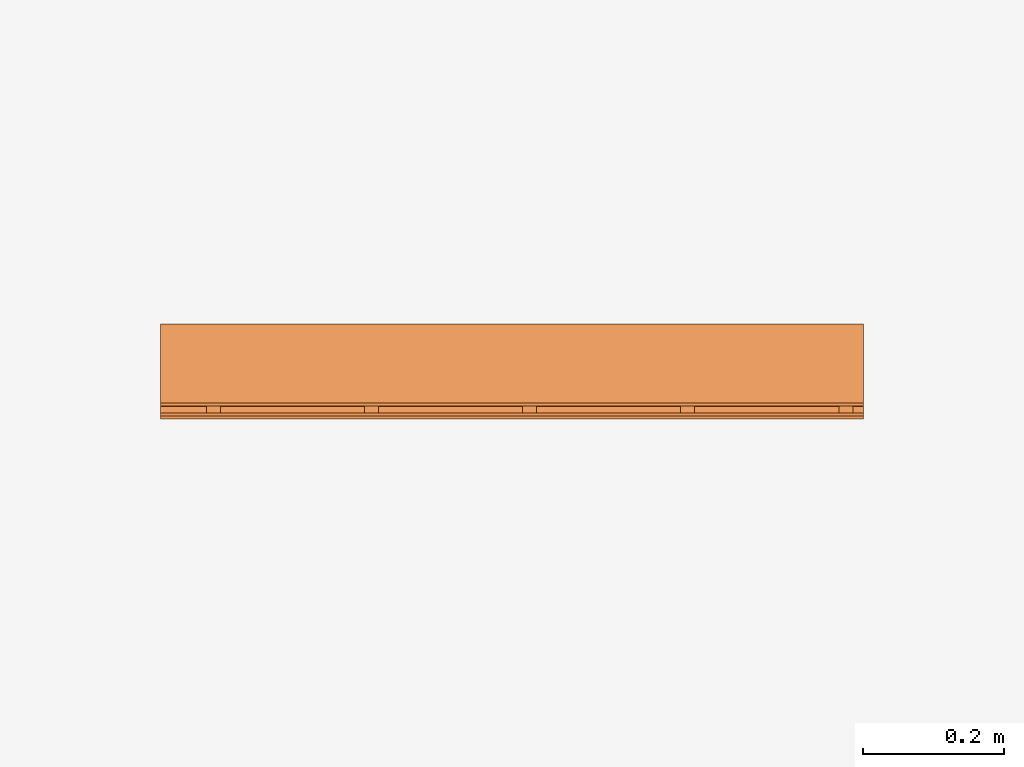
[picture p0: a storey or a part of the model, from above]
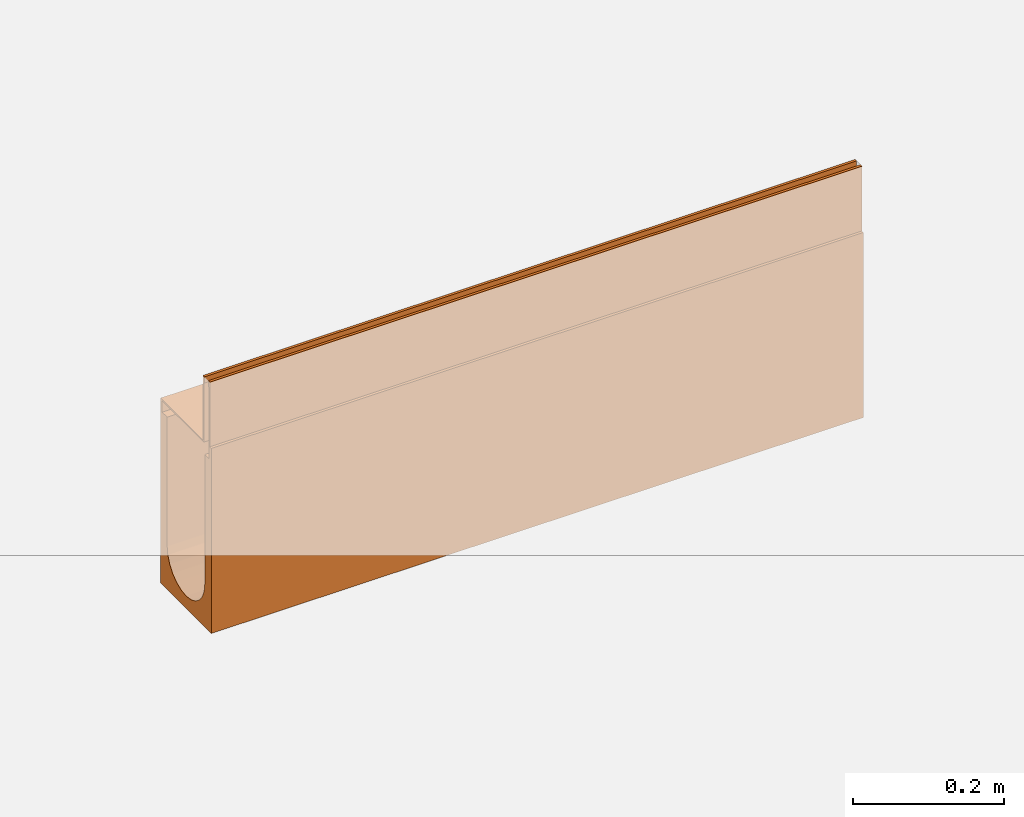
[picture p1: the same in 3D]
Properties of the parts of a building model (IFC2X3)

# File
Description: ViewDefinition [CoordinationView]
File name: 23300 - No 30.0 Constant Depth Channel - 1000mm LG - Invert Depth 280mm.ifc
Time: 2013-10-31T17:34:53
Written by: Autodesk Revit 2013
Made in: 20120221_2030(x64)

# IfcProject, Project Number
LongName: Project Name; Phase: Project Status

# IfcSite, Default
RefLatitude: 42, 21, 30, 344238; RefLongitude: -71, -3, -35, -194702; RefElevation: 0 mm

# IfcBuilding
Pset_BuildingCommon - NumberOfStoreys: 1
Other - Project Name: Project Name; Project Status: Project Status; Project Number: Project Number; Project Address: ## Street City, State Zip; Project Issue Date: Issue Date; Client Name: Owner

# IfcBuildingStorey, Level 1
LongName: Level 1; Elevation: 0 mm
Graphics - Symbol: M_Level Head - Circle: M_Level Head - Circle; Line Weight: 1; Color: 0; Symbol at End 1 Default: no; Line Pattern: Center; Symbol at End 2 Default: yes
Constraints - Elevation Base: 0; Elevation: 0 mm
Identity Data - Name: Level 1; Structural: no; Building Story: yes
Dimensions - Computation Height: 0 mm

# IfcBuildingElementProxy: 23300 - No 30.0 Constant Depth Channel - 1000mm LG - Invert Depth 280mm, Civil-Drainage-Channel-ACO-MultiDrain-M100D-Brickslot-Channel-System:23300 - No 30.0 Constant Depth Channel - 1000mm LG - Invert Depth 280mm:23300 - No 30.0 Constant Depth Channel - 1000mm LG - Invert Depth 280mm:196059
In: Level 1
Material: Steel, Galvanized, Vienite® Synthetic Resin Concrete
Phasing - Phase Created: New Construction
Construction - 23465_Load Class D400_Brickslot Grating_Galvanized Steel_1000mm Long: yes; 23467_Load Class D400_Brickslot Access Unit_Galvanised Steel_500mm Long: no; 23460_Load Class C250_Brickslot Grating_Galvanized Steel_1000mm Long: no; 23462_Load Class C250_Brickslot Access Unit_Galvanised Steel_500mm Long: no; 23461_Load Class C250_Brickslot Grating_Galvanized Steel_500mm Long: no; 23404_Universal Endcap (Male End): no; 23404_Universal Endcap (Female End): no; 23466_Load Class D400_Brickslot Grating_Galvanized Steel_500mm Long: no; Constant Depth Junction Channel: no; Shallow Depth Channel: no; Constant Depth Channel: yes; Sloping Channel: no; Shallow Depth Channel with seal: no; 23410_Sump Unit: no
Dimensions - FloorCut_Length: -1000 mm; Custom_Void_length: 0 mm; Length: 1000 mm; Brickslot Void Length: 1000 mm; Volume: 13742822 mm3; Brickslot Access Unit Void Depth: -6500 mm; EndCap Position: 1000 mm; Brickslot Access Unit Void Bottom Depth: -6605 mm; Brickslot Void Depth: 0 mm; Access_Custom_Void_Length: 0 mm; FloorCut_Width: 135 mm; Brickslot Access Unit Floor Cut Length: 500 mm; SlopingEndInvertDepth: 180 mm; Floor Cut Gap: 105 mm; GratingLength: -1000 mm; ShallowInvDepth: 55 mm; Length Drain: -1000 mm; SlopingInvertDepth: 175 mm; Depth: 300 mm; SlopingOverallDepth: 245 mm; SlopingEndOverallDepth: 250 mm; InvDepth: 230 mm; FloorCut_Depth: 300 mm; EndCap_Height: 300 mm; ShallowOverallDepth: 75 mm
Constraints - Level: Level: Level 1; Moves With Nearby Elements: no
Pset_BuildingElementProxyCommon - Reference: 23300 - No 30.0 Constant Depth Channel - 1000mm LG - Invert Depth 280mm
Model Properties - Brickslot Access Unit Product code 23462: Load Class C250 - Brickslot Access Unit Galvanised Steel - 500mm long x 105mm high - 10mm Slot - Intake area - 10000mm²/m - 6.4 Kg; Brickslot Grating Product code 23461: Load Class C250 - Brickslot Galvanised Steel - 500mm long x 105mm high - 10mm Slot - Intake area - 10000mm²/m -3.3 Kg; Brickslot Grating Product code 23460: Load Class C250 - Brickslot Galvanised Steel - 1000mm long x 105mm high - 10mm Slot - Intake area - 10000mm²/m - 6.6 Kg; Brickslot Access Unit Product code 23467: Load Class D400 - Brickslot Access Unit Galvanised Steel - 500mm long x 105mm high - 10mm Slot - Intake area - 10000mm²/m - 6.4 Kg; Brickslot Grating Product code 23465: Load Class D400 - Brickslot Galvanised Steel - 1000mm long x 105mm high - 10mm Slot - Intake area - 10000mm²/m - 6.6 Kg; End Cap Product code 23404: No 306 Universal End Cap - 135mm wide x 300mm long - Spigot Ø110mm x 50mm long - Silver - Polypropylene - 0.16kg; Brickslot Grating Product code 23466: Load Class D400 - Brickslot Galvanised Steel - 500mm long x 105mm high - 10mm Slot - Intake area - 10000mm²/m - 3.3 Kg
Green Building Properties - Channel Recycled Material Content: 20% minimum; Edge Rail Recyclable: Fully recyclable; Channel Recyclable: Fully recyclable; Edge Rail Recycled Material Content: Between 40% - 90%
Identity Data - Product Code: 23300; Watermark 2: This file is water marked and users are prohibited to reproduce, adapt, distribute this information; OmniClass Number: 23.70.50.24; Watermarked With: BIM Manager Premium Suite; Maintenance guidelines: http://www.aco.co.uk/download.php?id=173; Watermark 1: This file is the property of ACO Technologies PLC; URL: www.aco.co.uk; Assembly Description: Rain Water Drainage; Model Description: Channel drainage system; e-mail Sales: customersupport@aco.co.uk; Product brochure: http://www.aco.co.uk/download.php?id=173; Price: POA - contact ACO; Telephone: +44 (0)1462 816666; Installation guidelines: http://www.aco.co.uk/download.php?id=173; Fax: +44 (0)1462 815895; Product Page URL: http://www.aco.co.uk/product_detail.php?id=58; e-mail Technical: technical@aco.co.uk; OmniClass Title: Rainwater Removal; Type Comments: ACO MultiDrain M100D 30.0 Constant Depth Channel 1000mm Long; Cost: 0; Address: ACO Business Park, Hitchin Road, Shefford, Bedfordshire, United Kingdom SG17 5TE; Manufacturer: ACO Technologies plc - ACO Water Management Division; Model: ACO MultiDrain MD Brickslot- M100D; Assembly Code: D2040
Materials and Finishes - Channel Colour: Brown; Channel Material: Vienite® Synthetic Resin Concrete; Edge Rail Colour: Silver; Edge Rail Material: Steel; Edge Rail Finish: Pre-galvanised
General - TagNumber: 0; SerialNumber: 0
Data - Installation - Concrete Grade: Refer to brochure; Concrete Surround Volume - Load Class D 400 - Concrete Pavement: 0.23m³/m; Product Dimensions: 1000mm x 135mm x 300mm (LxWxH); Invert Depth: 280mm; Product Standard: BS EN 1433:2002, CE marked; ACO Hydraulic Design Software: http://www.acodesign.co.uk; Load Class: A 15 - D 400; Channel C.S.A: 0.021m²; Concrete Surround Volume - Load Class A 15 - Concrete Pavement: 0.10m³/m; Product Weight: 22.4 Kg; Concrete Surround Volume - Load Class B 125 - C 250 - Concrete Pavement: 0.16m³/m; Pre-formed Outlet Ø: N/A; Hydraulic Performance: http://www.aco.co.uk/download.php?id=173
Other - Watermarked By: www.aco.co.uk; Revision: 1; Created By: www.aco.co.uk

# IfcOpeningElement: Recess (2)
In: Level 1
Constraints - Level: Level: Level 1; Height Offset From Level: 0 mm; Related to Mass: no; Room Bounding: yes
Dimensions - Perimeter: 20000 mm; Area: 25000000 mm2; Volume: 24957610000 mm3; Thickness: 1000 mm
Structural - Structural: no; Enable Analytical Model: no
Phasing - Phase Created: New Construction
Analytical Properties - Thermal Resistance (R): 1.19474; Thermal mass: 1359800; Roughness: 1; Absorptance: 0.1; Heat Transfer Coefficient (U): 0.837
Graphics - Coarse Scale Fill Color: 0
Construction - Default Thickness: 1000 mm; Function: 0
Materials and Finishes - Structural Material: Earth

# IfcSlab: Floor:Generic Floor - 1000mm, Floor:Generic Floor - 1000mm:193825
In: Level 1
PredefinedType: FLOOR; Material: Earth 1000 mm
Constraints - Level: Level: Level 1; Height Offset From Level: 0 mm; Related to Mass: no; Room Bounding: yes
Dimensions - Perimeter: 20000 mm; Area: 25000000 mm2; Volume: 24957610000 mm3; Thickness: 1000 mm
Structural - Structural: no; Enable Analytical Model: no
Phasing - Phase Created: New Construction
Pset_SlabCommon - Reference: Generic Floor - 1000mm; IsExternal: no; LoadBearing: yes
Analytical Properties - Thermal Resistance (R): 1.19474; Thermal mass: 1359800; Roughness: 1; Absorptance: 0.1; Heat Transfer Coefficient (U): 0.837
Graphics - Coarse Scale Fill Color: 0
Construction - Default Thickness: 1000 mm; Function: 0
Materials and Finishes - Structural Material: Earth
